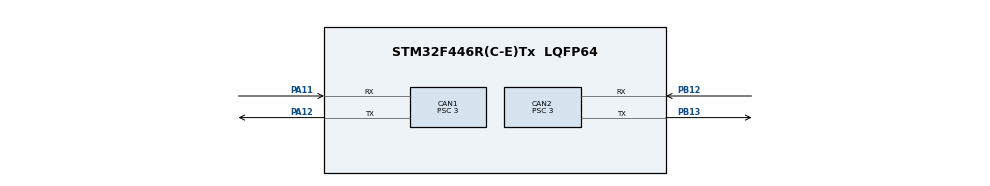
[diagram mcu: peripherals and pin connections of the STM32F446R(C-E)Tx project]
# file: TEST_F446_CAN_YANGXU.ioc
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CAN1.BS1=CAN_BS1_12TQ
CAN1.BS2=CAN_BS2_2TQ
CAN1.CalculateBaudRate=1000000
CAN1.CalculateTimeBit=1000
CAN1.CalculateTimeQuantum=66.66666666666666
CAN1.Prescaler=3
CAN2.BS1=CAN_BS1_12TQ
CAN2.BS2=CAN_BS2_2TQ
CAN2.CalculateBaudRate=1000000
CAN2.CalculateTimeBit=1000
CAN2.CalculateTimeQuantum=66.66666666666666
CAN2.Prescaler=3
Mcu.Family=STM32F4
Mcu.Name=STM32F446R(C-E)Tx
Mcu.Package=LQFP64
NVIC.CAN1_RX0_IRQn=true\:0\:0\:false\:false\:true\:true\:true\:true
NVIC.CAN1_SCE_IRQn=true\:0\:0\:false\:false\:true\:true\:true\:true
NVIC.CAN2_RX1_IRQn=true\:0\:0\:false\:false\:true\:true\:true\:true
NVIC.CAN2_SCE_IRQn=true\:0\:0\:false\:false\:true\:true\:true\:true
NVIC.PriorityGroup=NVIC_PRIORITYGROUP_4
PA11.Mode=CAN_Activate
PA11.Signal=CAN1_RX
PA12.Mode=CAN_Activate
PA12.Signal=CAN1_TX
PA13.Mode=Serial_Wire
PA13.Signal=SYS_JTMS-SWDIO
PA14.Mode=Serial_Wire
PA14.Signal=SYS_JTCK-SWCLK
PB12.Mode=CAN_Activate
PB12.Signal=CAN2_RX
PB13.Mode=CAN_Activate
PB13.Signal=CAN2_TX
PH0-OSC_IN.Mode=HSE-External-Oscillator
PH0-OSC_IN.Signal=RCC_OSC_IN
PH1-OSC_OUT.Mode=HSE-External-Oscillator
PH1-OSC_OUT.Signal=RCC_OSC_OUT
ProjectManager.HeapSize=0x200
ProjectManager.StackSize=0x400
ProjectManager.TargetToolchain=MDK-ARM V5.32
RCC.AHBFreq_Value=180000000
RCC.APB1CLKDivider=RCC_HCLK_DIV4
RCC.APB1Freq_Value=45000000
RCC.APB1TimFreq_Value=90000000
RCC.APB2CLKDivider=RCC_HCLK_DIV2
RCC.APB2Freq_Value=90000000
RCC.APB2TimFreq_Value=180000000
RCC.CortexFreq_Value=180000000
RCC.HCLKFreq_Value=180000000
RCC.PLLM=15
RCC.PLLN=216
RCC.PLLSourceVirtual=RCC_PLLSOURCE_HSE
RCC.SYSCLKFreq_VALUE=180000000
RCC.SYSCLKSource=RCC_SYSCLKSOURCE_PLLRCLK
RCC.USBFreq_Value=180000000
RCC.VCOOutputFreq_Value=360000000
board=custom

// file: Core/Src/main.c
/* USER CODE BEGIN Header */
/**
  ******************************************************************************
  * @file           : main.c
  * @brief          : Main program body
  ******************************************************************************
  * @attention
  *
  * Copyright (c) 2023 STMicroelectronics.
  * All rights reserved.
  *
  * This software is licensed under terms that can be found in the LICENSE file
  * in the root directory of this software component.
  * If no LICENSE file comes with this software, it is provided AS-IS.
  *
  ******************************************************************************
  */
/* USER CODE END Header */
#include "main.h"
#include "can.h"
#include "gpio.h"

/* USER CODE BEGIN Includes */
#include "can_bsp.h"
#include "RM3508.h"
/* USER CODE END Includes */

/* USER CODE BEGIN PTD */
int flag=0;
/* USER CODE END PTD */

void SystemClock_Config(void);

int main(void)
{

  /* MCU Configuration--------------------------------------------------------*/

  /* Reset of all peripherals, Initializes the Flash interface and the Systick. */
  HAL_Init();

  /* Configure the system clock */
  SystemClock_Config();

  /* Initialize all configured peripherals */
  MX_GPIO_Init();
  MX_CAN1_Init();
  MX_CAN2_Init();
  /* USER CODE BEGIN 2 */
	CAN_Init(&hcan1);
	CAN_Init(&hcan2);
  /* USER CODE END 2 */

  /* Infinite loop */
  while (1)
  {

    /* USER CODE BEGIN 3 */
<<<<<<< HEAD
		RM3508_Set_Speed(2000,0x02);
=======
		RM3508_Set_Speed(4000,1);
>>>>>>> a7dc6b2230f0a18941949e553be245e90850b693

		HAL_Delay(100);
  }
  /* USER CODE END 3 */
}

void SystemClock_Config(void)
{
  RCC_OscInitTypeDef RCC_OscInitStruct = {0};
  RCC_ClkInitTypeDef RCC_ClkInitStruct = {0};

  /** Configure the main internal regulator output voltage
  */
  __HAL_RCC_PWR_CLK_ENABLE();
  __HAL_PWR_VOLTAGESCALING_CONFIG(PWR_REGULATOR_VOLTAGE_SCALE2);

  /** Initializes the RCC Oscillators according to the specified parameters
  * in the RCC_OscInitTypeDef structure.
  */
  RCC_OscInitStruct.OscillatorType = RCC_OSCILLATORTYPE_HSE;
  RCC_OscInitStruct.HSEState = RCC_HSE_ON;
  RCC_OscInitStruct.PLL.PLLState = RCC_PLL_ON;
  RCC_OscInitStruct.PLL.PLLSource = RCC_PLLSOURCE_HSE;
  RCC_OscInitStruct.PLL.PLLM = 19;
  RCC_OscInitStruct.PLL.PLLN = 216;
  RCC_OscInitStruct.PLL.PLLP = RCC_PLLP_DIV2;
  RCC_OscInitStruct.PLL.PLLQ = 2;
  RCC_OscInitStruct.PLL.PLLR = 2;
  if (HAL_RCC_OscConfig(&RCC_OscInitStruct) != HAL_OK)
  {
    Error_Handler();
  }

  /** Initializes the CPU, AHB and APB buses clocks
  */
  RCC_ClkInitStruct.ClockType = RCC_CLOCKTYPE_HCLK|RCC_CLOCKTYPE_SYSCLK
                              |RCC_CLOCKTYPE_PCLK1|RCC_CLOCKTYPE_PCLK2;
  RCC_ClkInitStruct.SYSCLKSource = RCC_SYSCLKSOURCE_PLLRCLK;
  RCC_ClkInitStruct.AHBCLKDivider = RCC_SYSCLK_DIV1;
  RCC_ClkInitStruct.APB1CLKDivider = RCC_HCLK_DIV4;
  RCC_ClkInitStruct.APB2CLKDivider = RCC_HCLK_DIV2;

  if (HAL_RCC_ClockConfig(&RCC_ClkInitStruct, FLASH_LATENCY_4) != HAL_OK)
  {
    Error_Handler();
  }
}

/* USER CODE BEGIN 4 */

/*FIFO0的回调函数*/
void HAL_CAN_RxFifo0MsgPendingCallback(CAN_HandleTypeDef *hcan)
{
	if(hcan->Instance == hcan1.Instance)
	{
		CAN_RxHeaderTypeDef RxMessage;
	uint8_t RxData[8] = {0};

	HAL_CAN_GetRxMessage(hcan, CAN_RX_FIFO0, &RxMessage, RxData);	//通过can协议，从FIFO0中读取RxData数据，这数据就是电调反馈的报文

	if(RxMessage.IDE==CAN_ID_STD)
		{
			if(RxMessage.StdId>=0x201&&RxMessage.StdId<=0x208)
			{
				RM3508_Get_Feedback(RxMessage.StdId, RxData);
			}

	/*自己写解析函数*/
		}

	}
}

void HAL_CAN_RxFifo1MsgPendingCallback(CAN_HandleTypeDef *hcan)
{
	if(hcan->Instance == hcan2.Instance)
	{
		CAN_RxHeaderTypeDef RxMessage;
		uint8_t RxData[8] = {0};

		HAL_CAN_GetRxMessage(hcan, CAN_RX_FIFO1, &RxMessage, RxData);

		if(RxMessage.IDE==CAN_ID_STD)
			{
				if(RxMessage.StdId>=0x201&&RxMessage.StdId<=0x208)
				{
					RM3508_Get_Feedback(RxMessage.StdId, RxData);
				}
			}
	/*自己写解析函数*/

	}
}

/* USER CODE END 4 */

void Error_Handler(void)
{
  __disable_irq();
  while (1)
  {
  }
}
